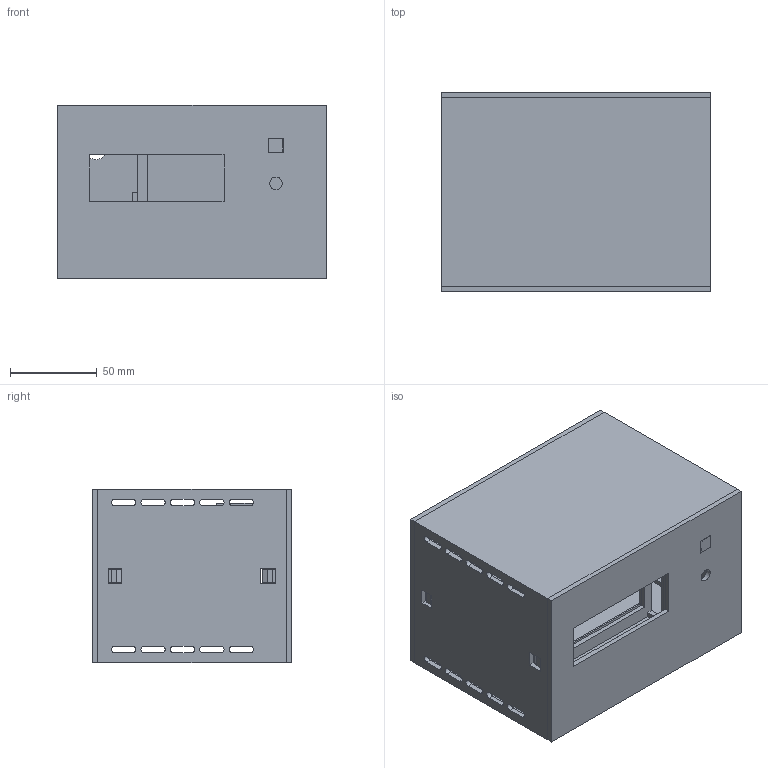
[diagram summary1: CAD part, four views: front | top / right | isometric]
STEP (ISO 10303-21) file: header records copied from the file, then geometry measured from it (millimetres).
FILE_DESCRIPTION(('Open CASCADE Model'),'2;1');
FILE_NAME('Open CASCADE Shape Model','2026-11-06T18:44:25',('Author'),( 'Open CASCADE'),'Open CASCADE STEP processor 7.8','Open CASCADE 7.8' ,'Unknown');
FILE_SCHEMA(('AUTOMOTIVE_DESIGN { 1 0 10303 214 1 1 1 1 }'));
Length unit declared in the file: millimetre
Products named in the file (7): Boitier_6_pieces_a_imprimer; 01_Coque_ouverte; 02_Facade_supports_LCD_A; 03_Berceau_B; 04_Panneau_arriere; 05_Fenetre_translucide; 06_Cassette_BH1750
Assembly tree (6 placements, depth 2):
  Boitier_6_pieces_a_imprimer
    01_Coque_ouverte
    02_Facade_supports_LCD_A
    03_Berceau_B
    04_Panneau_arriere
    05_Fenetre_translucide
    06_Cassette_BH1750
Bounding box: 155 x 115 x 100 mm (x, y, z)
Volume: 285702.2 mm3; surface area: 221049.1 mm2
Topology: 6 solids, 6 shells, 582 faces, 1644 edges, 1094 vertices
Faces by surface type: plane 537, cylinder 45
Full cylindrical faces by diameter (mm): 7.2 x1, 12.4 x1, 12.5 x2, 16 x1
Entity records: 39167 total; most frequent: CARTESIAN_POINT 7687, DIRECTION 5128, LINE 3680, VECTOR 3680, ORIENTED_EDGE 3288, PCURVE 3288, DEFINITIONAL_REPRESENTATION 3288, EDGE_CURVE 1644
